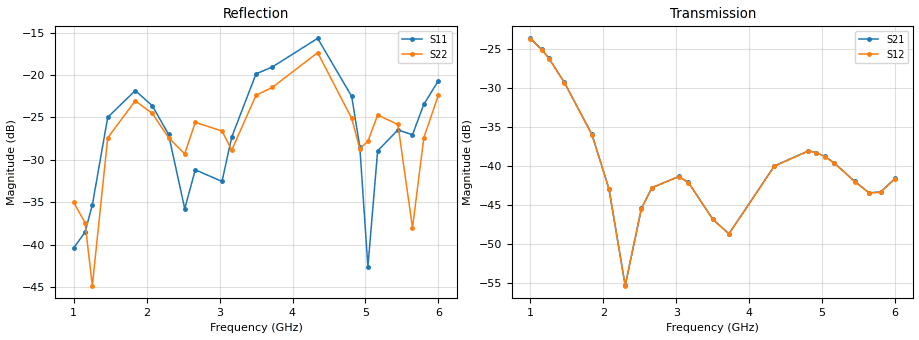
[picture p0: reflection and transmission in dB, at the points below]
!Agilent Technologies,E8364B,MY43040528,A.07.50.67
!Agilent E8364B: A.07.50.67
!Date: Sunday, March 01, 2026 21:15:40
!Correction: S11(Full 2 Port(1,2))
!S21(Full 2 Port(1,2))
!S12(Full 2 Port(1,2))
!S22(Full 2 Port(1,2))
!S2P File: Measurements: S11, S21, S12, S22:
# Hz S  dB  R 50
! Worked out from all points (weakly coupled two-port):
!   451 points, 1 GHz to 6 GHz, reference 50 ohm
!   highest |S21| = -23.63 dB at 1 GHz (marker M1); lowest = -55.3 dB at 2.3 GHz (marker M2)
!   lowest |S11| = -42.6 dB at 5.033 GHz (marker M3), VSWR 1.01, Z = 50.1 - j0.736 ohm
!   |S11| at or under -10 dB: start of sweep to end of sweep
!   |S22| runs from -44.9 to -17.0 dB; largest |S21 - S12| = 0.00023
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1e9  -40.40 83.6  -23.63 148.6  -23.66 148.6  -35.02 17.2
1.155556e9  -38.54 135.9  -25.05 58.6  -25.08 58.6  -37.41 21.3
1.255556e9  -35.33 165.0  -26.19 1.0  -26.22 1.0  -44.85 67.2
1.466667e9  -24.98 153.7  -29.27 -117.6  -29.29 -117.6  -27.40 87.2
1.844444e9  -21.83 86.8  -35.93 37.7  -35.95 37.8  -23.04 -0.5
2.077778e9  -23.62 57.1  -42.88 -85.3  -42.91 -85.2  -24.53 -37.6
2.3e9  -26.99 32.4  -55.25 -132.5  -55.29 -132.2  -27.38 -63.5
2.522222e9  -35.77 50.7  -45.39 171.4  -45.43 171.6  -29.30 -50.9
2.666667e9  -31.18 82.7  -42.74 96.1  -42.76 96.0  -25.58 -56.6
3.033333e9  -32.55 80.5  -41.31 -102.4  -41.34 -102.4  -26.60 -117.3
3.166667e9  -27.31 104.7  -42.06 -174.4  -42.10 -174.4  -28.85 -105.4
3.5e9  -19.85 60.8  -46.76 22.7  -46.78 22.7  -22.38 -123.2
3.722222e9  -19.05 38.7  -48.64 -53.3  -48.69 -53.1  -21.46 -144.6
4.344444e9  -15.67 -40.8  -39.97 12.7  -40.00 12.8  -17.36 113.7
4.811111e9  -22.52 -121.3  -38.03 106.5  -38.06 106.6  -25.11 30.3
4.922222e9  -28.48 -138.1  -38.25 40.6  -38.28 40.7  -28.70 33.3
5.033333e9  -42.63 -83.7  -38.73 -25.9  -38.76 -25.9  -27.81 48.9
5.166667e9  -28.95 -33.7  -39.57 -106.8  -39.60 -106.8  -24.71 36.0
5.444444e9  -26.47 -70.1  -41.92 75.3  -41.96 75.3  -25.83 -28.1
5.644444e9  -27.04 -55.4  -43.40 -65.9  -43.44 -65.8  -38.02 -11.9
5.8e9  -23.45 -55.3  -43.29 -179.5  -43.33 -179.4  -27.40 26.6
6e9  -20.66 -74.7  -41.56 41.4  -41.60 41.5  -22.34 -9.0
